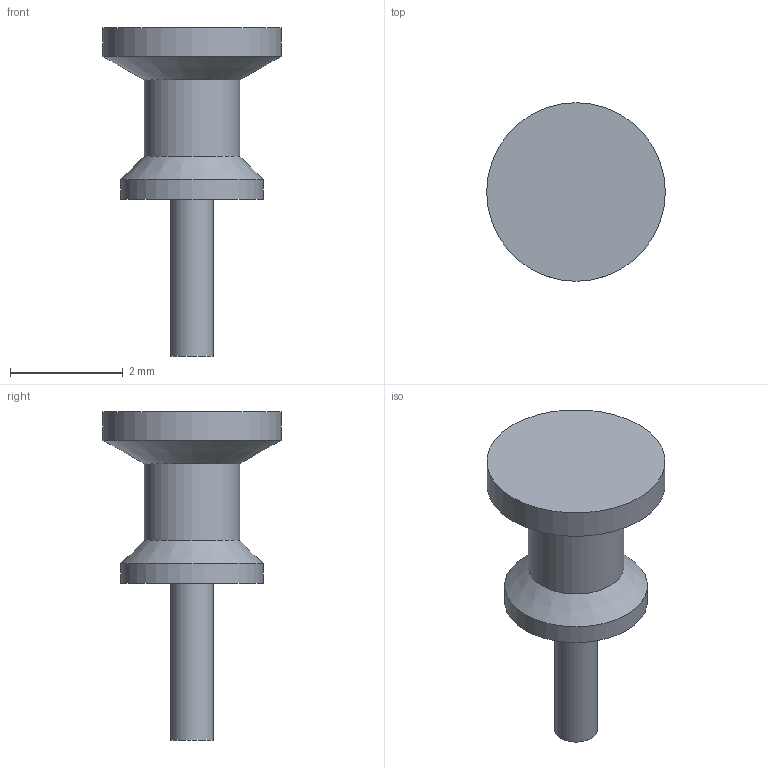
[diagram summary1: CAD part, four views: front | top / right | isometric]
STEP (ISO 10303-21) file: header records copied from the file, then geometry measured from it (millimetres).
FILE_DESCRIPTION(('Open CASCADE Model'),'2;1');
FILE_NAME('Open CASCADE Shape Model','2026-10-14T21:49:17',('Author'),( 'Open CASCADE'),'Open CASCADE STEP processor 7.9','Open CASCADE 7.9' ,'Unknown');
FILE_SCHEMA(('AUTOMOTIVE_DESIGN { 1 0 10303 214 1 1 1 1 }'));
Length unit declared in the file: millimetre
Products named in the file (1): Open CASCADE STEP translator 7.9 5
Bounding box: 3.17 x 3.17 x 5.84 mm (x, y, z)
Volume: 13.6 mm3; surface area: 45.2 mm2
Topology: 1 solids, 1 shells, 9 faces, 14 edges, 8 vertices
Faces by surface type: cylinder 4, plane 3, cone 2
Full cylindrical faces by diameter (mm): 0.762 x1, 1.702 x1, 2.54 x1, 3.175 x1
Entity records: 396 total; most frequent: DIRECTION 70, CARTESIAN_POINT 60, LINE 30, VECTOR 30, ORIENTED_EDGE 28, PCURVE 28, DEFINITIONAL_REPRESENTATION 28, AXIS2_PLACEMENT_3D 18
One B-rep face of a CAD part: STEP entity #419.
In plain terms, the planar face has unit normal (0, 0, 1).
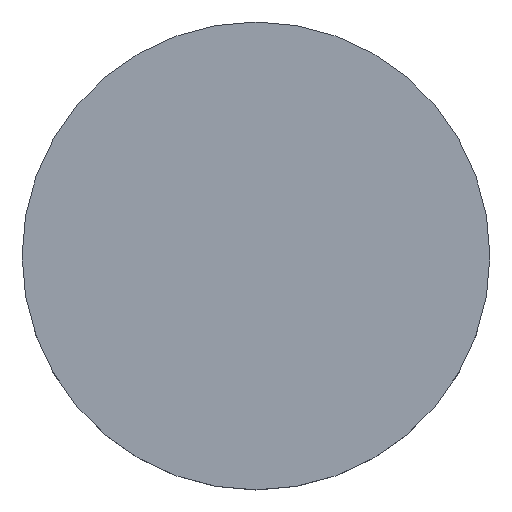
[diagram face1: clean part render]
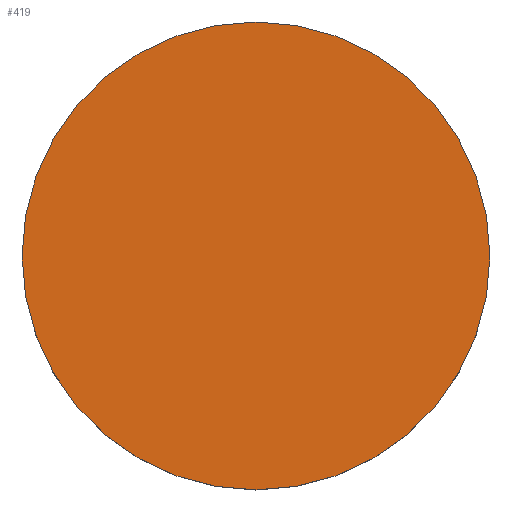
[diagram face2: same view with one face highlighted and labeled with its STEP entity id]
Its self-contained STEP definition (entity closure, numbers rounded to 3 decimals):
#352 = CYLINDRICAL_SURFACE('',#353,1.588);
#353 = AXIS2_PLACEMENT_3D('',#354,#355,#356);
#354 = CARTESIAN_POINT('',(-5.25,-16.969,2.087));
#355 = DIRECTION('',(0.,0.,1.));
#356 = DIRECTION('',(1.,0.,-0.));
#370 = VERTEX_POINT('',#371);
#371 = CARTESIAN_POINT('',(-3.663,-16.969,2.595));
#392 = EDGE_CURVE('',#370,#370,#393,.T.);
#393 = SURFACE_CURVE('',#394,(#399,#406),.PCURVE_S1.);
#394 = CIRCLE('',#395,1.588);
#395 = AXIS2_PLACEMENT_3D('',#396,#397,#398);
#396 = CARTESIAN_POINT('',(-5.25,-16.969,2.595));
#397 = DIRECTION('',(0.,0.,1.));
#398 = DIRECTION('',(1.,0.,-0.));
#399 = PCURVE('',#352,#400);
#400 = DEFINITIONAL_REPRESENTATION('',(#401),#405);
#401 = LINE('',#402,#403);
#402 = CARTESIAN_POINT('',(0.,0.508));
#403 = VECTOR('',#404,1.);
#404 = DIRECTION('',(1.,0.));
#405 = ( GEOMETRIC_REPRESENTATION_CONTEXT(2) 
PARAMETRIC_REPRESENTATION_CONTEXT() REPRESENTATION_CONTEXT('2D SPACE',''
  ) );
#406 = PCURVE('',#407,#412);
#407 = PLANE('',#408);
#408 = AXIS2_PLACEMENT_3D('',#409,#410,#411);
#409 = CARTESIAN_POINT('',(-5.25,-16.969,2.595));
#410 = DIRECTION('',(0.,0.,1.));
#411 = DIRECTION('',(1.,0.,-0.));
#412 = DEFINITIONAL_REPRESENTATION('',(#413),#417);
#413 = CIRCLE('',#414,1.588);
#414 = AXIS2_PLACEMENT_2D('',#415,#416);
#415 = CARTESIAN_POINT('',(0.,0.));
#416 = DIRECTION('',(1.,0.));
#417 = ( GEOMETRIC_REPRESENTATION_CONTEXT(2) 
PARAMETRIC_REPRESENTATION_CONTEXT() REPRESENTATION_CONTEXT('2D SPACE',''
  ) );
#419 = ADVANCED_FACE('',(#420),#407,.T.);
#420 = FACE_BOUND('',#421,.T.);
#421 = EDGE_LOOP('',(#422));
#422 = ORIENTED_EDGE('',*,*,#392,.T.);
